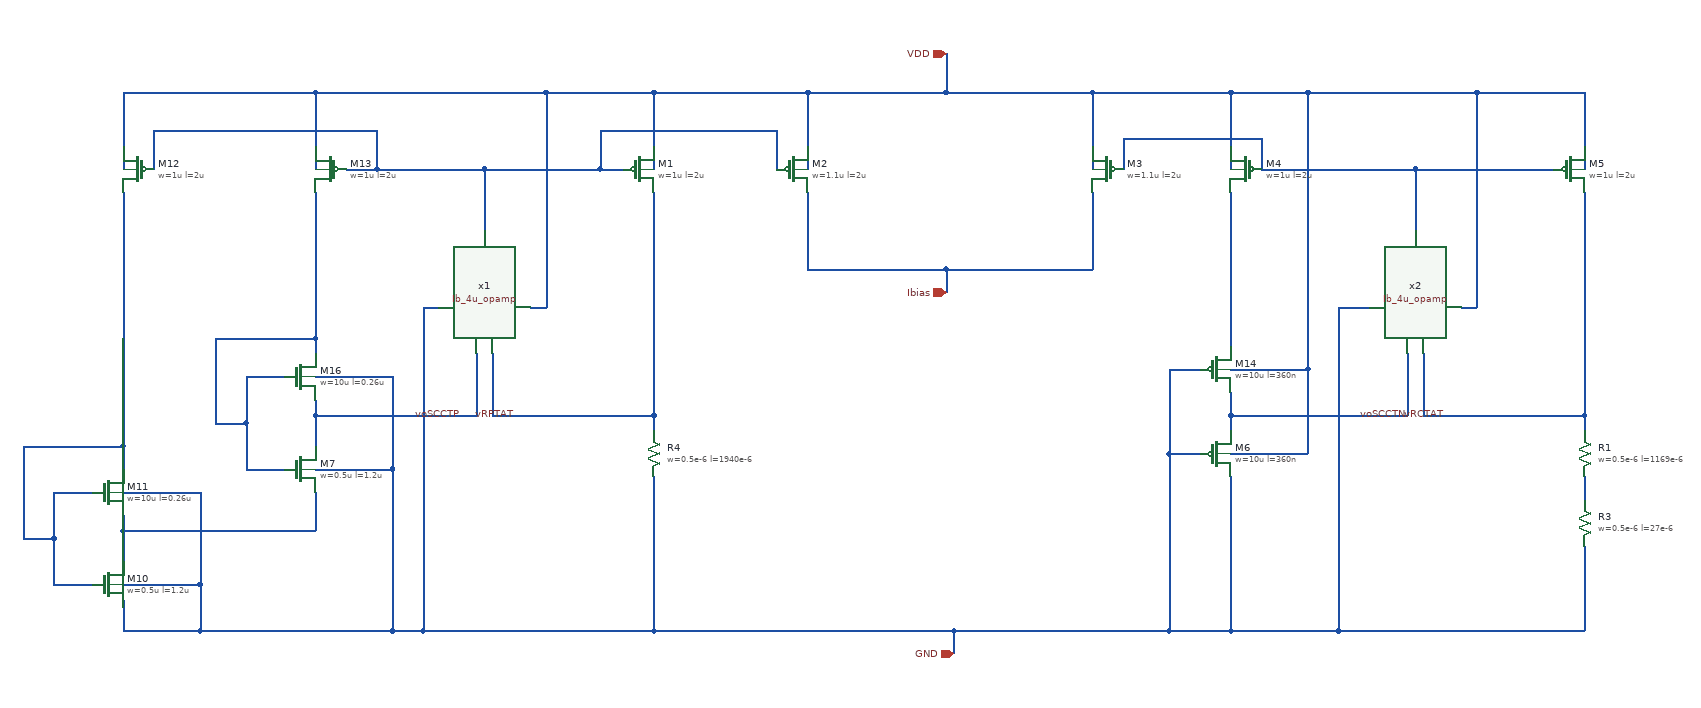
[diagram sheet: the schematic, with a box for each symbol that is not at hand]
v {xschem version=3.4.6 file_version=1.2}
G {}
K {}
V {}
S {}
E {}
N 2310 -980 2310 -940 {lab=vg_2}
N 2190 -680 2230 -680 {lab=GND}
N 2190 -570 2230 -570 {lab=GND}
N 2270 -620 2270 -600 {lab=voSCCTN}
N 2510 -940 2510 -860 {lab=vg_2}
N 2310 -940 2510 -940 {lab=vg_2}
N 1720 -1040 1720 -940 {lab=VDD}
N 2090 -1040 2090 -940 {lab=VDD}
N 2270 -1040 2270 -940 {lab=VDD}
N 2730 -1040 2730 -940 {lab=VDD}
N 830 -1040 1080 -1040 {lab=VDD}
N 1520 -1040 1520 -940 {lab=VDD}
N 1380 -1040 1520 -1040 {lab=VDD}
N 1450 -940 1480 -940 {lab=vg_1}
N 1450 -990 1450 -940 {lab=vg_1}
N 1680 -990 1680 -940 {lab=vg_1}
N 2130 -980 2130 -940 {lab=vg_2}
N 1300 -940 1450 -940 {lab=vg_1}
N 1080 -1040 1080 -940 {lab=VDD}
N 1300 -940 1300 -860 {lab=vg_1}
N 1160 -940 1300 -940 {lab=vg_1}
N 1360 -760 1380 -760 {lab=VDD}
N 1380 -1040 1380 -760 {lab=VDD}
N 1080 -1040 1380 -1040 {lab=VDD}
N 1080 -620 1080 -580 {lab=voSCCTP}
N 1080 -670 1180 -670 {lab=GND}
N 1180 -670 1180 -550 {lab=GND}
N 1080 -550 1180 -550 {lab=GND}
N 990 -670 1040 -670 {lab=#net1}
N 990 -610 990 -550 {lab=#net1}
N 990 -550 1040 -550 {lab=#net1}
N 1080 -720 1080 -700 {lab=#net1}
N 950 -610 990 -610 {lab=#net1}
N 990 -670 990 -610 {lab=#net1}
N 950 -720 950 -610 {lab=#net1}
N 950 -720 1080 -720 {lab=#net1}
N 1080 -910 1080 -720 {lab=#net1}
N 1080 -620 1290 -620 {lab=voSCCTP}
N 1080 -640 1080 -620 {lab=voSCCTP}
N 1290 -700 1290 -620 {lab=voSCCTP}
N 830 -470 830 -430 {lab=#net2}
N 830 -520 930 -520 {lab=GND}
N 930 -520 930 -400 {lab=GND}
N 830 -400 930 -400 {lab=GND}
N 740 -520 790 -520 {lab=#net3}
N 740 -460 740 -400 {lab=#net3}
N 740 -400 790 -400 {lab=#net3}
N 700 -460 740 -460 {lab=#net3}
N 740 -520 740 -460 {lab=#net3}
N 830 -470 1080 -470 {lab=#net2}
N 830 -490 830 -470 {lab=#net2}
N 1080 -520 1080 -470 {lab=#net2}
N 830 -580 830 -550 {lab=#net3}
N 830 -1040 830 -940 {lab=VDD}
N 870 -990 870 -940 {lab=vg_1}
N 870 -990 1160 -990 {lab=vg_1}
N 1160 -990 1160 -940 {lab=vg_1}
N 1120 -940 1160 -940 {lab=vg_1}
N 830 -380 830 -340 {lab=GND}
N 700 -580 700 -460 {lab=#net3}
N 700 -580 830 -580 {lab=#net3}
N 830 -910 830 -580 {lab=#net3}
N 2190 -680 2190 -570 {lab=GND}
N 2410 -340 2730 -340 {lab=GND}
N 1180 -550 1180 -340 {lab=GND}
N 930 -340 1180 -340 {lab=GND}
N 930 -400 930 -340 {lab=GND}
N 830 -340 930 -340 {lab=GND}
N 2270 -570 2370 -570 {lab=VDD}
N 2590 -1040 2730 -1040 {lab=VDD}
N 1520 -620 1520 -600 {lab=vRPTAT}
N 1520 -540 1520 -340 {lab=GND}
N 1220 -340 1520 -340 {lab=GND}
N 1310 -700 1310 -620 {lab=vRPTAT}
N 1310 -620 1520 -620 {lab=vRPTAT}
N 1520 -910 1520 -620 {lab=vRPTAT}
N 2730 -620 2730 -600 {lab=vRCTAT}
N 2520 -620 2730 -620 {lab=vRCTAT}
N 2730 -910 2730 -620 {lab=vRCTAT}
N 2520 -700 2520 -620 {lab=vRCTAT}
N 2500 -700 2500 -620 {lab=voSCCTN}
N 2270 -910 2270 -710 {lab=#net4}
N 2270 -540 2270 -340 {lab=GND}
N 2270 -620 2500 -620 {lab=voSCCTN}
N 2270 -650 2270 -620 {lab=voSCCTN}
N 2370 -680 2370 -570 {lab=VDD}
N 2270 -1040 2370 -1040 {lab=VDD}
N 2410 -760 2450 -760 {lab=GND}
N 2410 -760 2410 -340 {lab=GND}
N 2270 -340 2410 -340 {lab=GND}
N 2570 -760 2590 -760 {lab=VDD}
N 2590 -1040 2590 -760 {lab=VDD}
N 2370 -1040 2590 -1040 {lab=VDD}
N 2190 -340 2270 -340 {lab=GND}
N 2190 -570 2190 -340 {lab=GND}
N 2130 -980 2310 -980 {lab=vg_2}
N 1450 -990 1680 -990 {lab=vg_1}
N 1520 -1040 1720 -1040 {lab=VDD}
N 2090 -1040 2270 -1040 {lab=VDD}
N 1900 -1040 2090 -1040 {lab=VDD}
N 1220 -760 1240 -760 {lab=GND}
N 1220 -760 1220 -340 {lab=GND}
N 1180 -340 1220 -340 {lab=GND}
N 2270 -680 2370 -680 {lab=VDD}
N 2370 -1040 2370 -680 {lab=VDD}
N 1900 -810 2090 -810 {lab=Ibias}
N 1720 -910 1720 -810 {lab=Ibias}
N 2090 -910 2090 -810 {lab=Ibias}
N 1900 -810 1900 -780 {lab=Ibias}
N 1720 -810 1900 -810 {lab=Ibias}
N 1900 -1090 1900 -1040 {lab=VDD}
N 1720 -1040 1900 -1040 {lab=VDD}
N 1910 -340 2190 -340 {lab=GND}
N 1910 -340 1910 -310 {lab=GND}
N 1520 -340 1910 -340 {lab=GND}
N 2730 -540 2730 -510 {lab=#net5}
N 2730 -450 2730 -340 {lab=GND}
N 2510 -940 2690 -940 {lab=vg_2}
C {iopin.sym} 1900 -1090 0 0 {name=p1 lab=VDD}
C {iopin.sym} 1910 -310 0 0 {name=p2 lab=GND}
C {iopin.sym} 1900 -780 0 0 {name=p3 lab=Ibias}
C {lab_pin.sym} 1270 -620 3 0 {name=p9 sig_type=std_logic lab=voSCCTP}
C {lab_pin.sym} 2500 -620 3 0 {name=p10 sig_type=std_logic lab=voSCCTN}
C {lab_pin.sym} 2550 -620 3 0 {name=p11 sig_type=std_logic lab=vRCTAT}
C {lab_pin.sym} 1340 -620 3 0 {name=p12 sig_type=std_logic lab=vRPTAT}
C {sg13g2_pr/sg13_lv_pmos.sym} 1500 -940 0 0 {name=M1
l=2u
w=1u
ng=1
m=1
model=sg13_lv_pmos
spiceprefix=X
}
C {sg13g2_pr/sg13_lv_pmos.sym} 1700 -940 0 0 {name=M2
l=2u
w=1.1u
ng=1
m=6
model=sg13_lv_pmos
spiceprefix=X
}
C {sg13g2_pr/sg13_lv_pmos.sym} 2110 -940 0 1 {name=M3
l=2u
w=1.1u
ng=1
m=6
model=sg13_lv_pmos
spiceprefix=X
}
C {sg13g2_pr/sg13_lv_pmos.sym} 2290 -940 0 1 {name=M4
l=2u
w=1u
ng=1
m=1
model=sg13_lv_pmos
spiceprefix=X
}
C {sg13g2_pr/sg13_lv_pmos.sym} 850 -940 0 1 {name=M12
l=2u
w=1u
ng=1
m=1
model=sg13_lv_pmos
spiceprefix=X
}
C {sg13g2_pr/sg13_lv_pmos.sym} 1100 -940 0 1 {name=M13
l=2u
w=1u
ng=1
m=1
model=sg13_lv_pmos
spiceprefix=X
}
C {sg13g2_pr/sg13_lv_pmos.sym} 2710 -940 0 0 {name=M5
l=2u
w=1u
ng=1
m=1
model=sg13_lv_pmos
spiceprefix=X
}
C {sg13g2_pr/sg13_lv_nmos.sym} 1060 -550 0 0 {name=M7
l=1.2u
w=0.5u
ng=1
m=1
model=sg13_lv_nmos
spiceprefix=X
}
C {sg13g2_pr/sg13_lv_nmos.sym} 810 -400 0 0 {name=M10
l=1.2u
w=0.5u
ng=1
m=1
model=sg13_lv_nmos
spiceprefix=X
}
C {sg13g2_pr/sg13_lv_nmos.sym} 810 -520 0 0 {name=M11
l=0.26u
w=10u
ng=1
m=30
model=sg13_lv_nmos
spiceprefix=X
}
C {sg13g2_pr/sg13_lv_nmos.sym} 1060 -670 0 0 {name=M16
l=0.26u
w=10u
ng=1
m=30
model=sg13_lv_nmos
spiceprefix=X
}
C {sg13g2_pr/sg13_lv_pmos.sym} 2250 -570 0 0 {name=M6
l=360n
w=10u
ng=1
m=20
model=sg13_lv_pmos
spiceprefix=X
}
C {sg13g2_pr/sg13_lv_pmos.sym} 2250 -680 0 0 {name=M14
l=360n
w=10u
ng=1
m=1
model=sg13_lv_pmos
spiceprefix=X
}
C {sg13g2_pr/rppd.sym} 1520 -570 0 0 {name=R4
w=0.5e-6
l=1940e-6
model=rppd
body=GND
spiceprefix=X
b=0
m=1
}
C {/shared/designs/SSDOR_w_startup_1V_ihp/Ib_4u/Ib_4u_opamp/Ib_4u_opamp.sym} 1240 -700 1 1 {name=x1}
C {/shared/designs/SSDOR_w_startup_1V_ihp/Ib_4u/Ib_4u_opamp/Ib_4u_opamp.sym} 2450 -700 1 1 {name=x2}
C {sg13g2_pr/rppd.sym} 2730 -570 0 0 {name=R1
w=0.5e-6
l=1169e-6
model=rppd
body=GND
spiceprefix=X
b=0
m=1
}
C {sg13g2_pr/rhigh.sym} 2730 -480 0 0 {name=R3
w=0.5e-6
l=27e-6
model=rhigh
body=GND
spiceprefix=X
b=0
m=1
}
